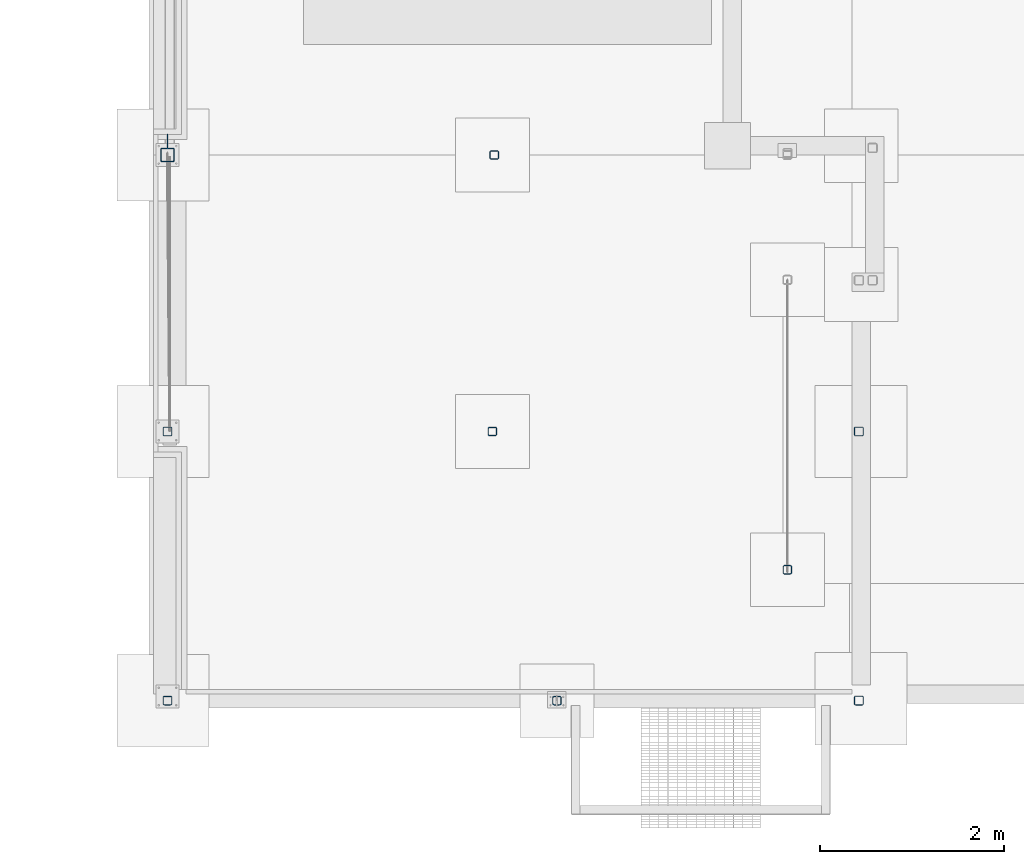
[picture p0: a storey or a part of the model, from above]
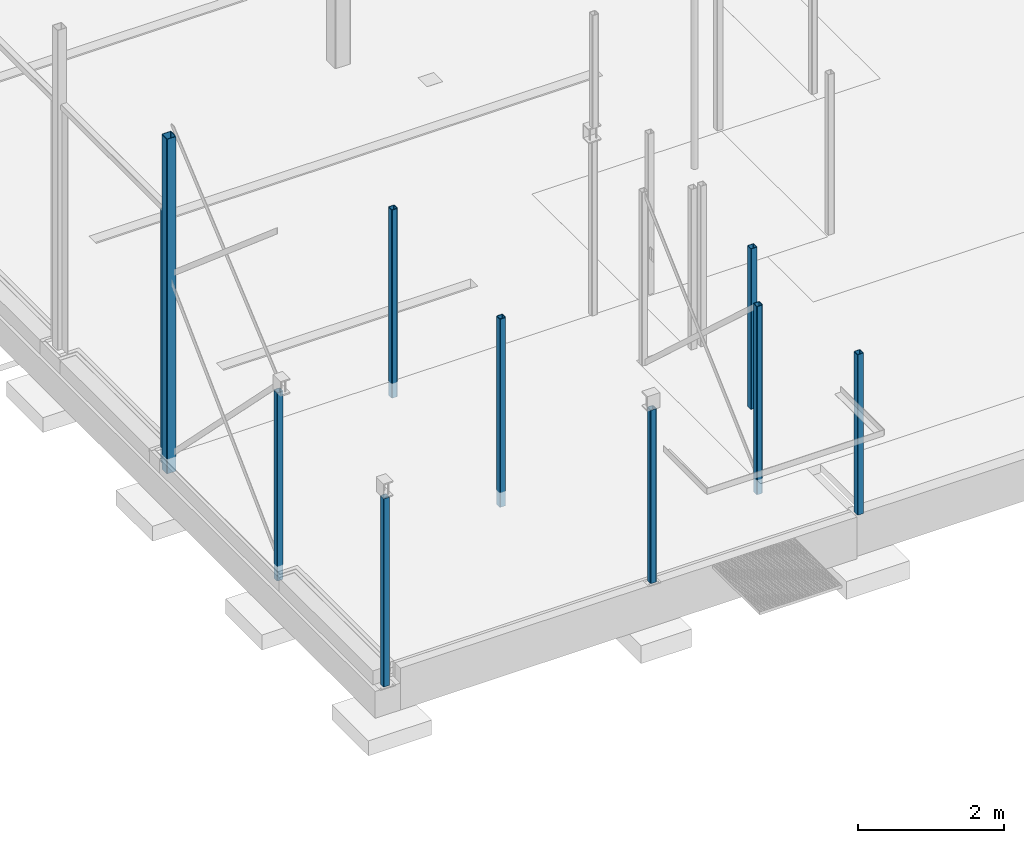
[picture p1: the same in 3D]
Properties of the parts of a building model (IFC2X3)

# File
Description: ViewDefinition [CoordinationView_V2.0]
File name: 17-036
Time: 2018-02-02T19:05:26
Written by: The EXPRESS Data Manager Version 5.02.0100.07 : 28 Aug 2013
Made in: 20170927_1515(x64) - Exporter 18.2.0.51 - Alternate UI 18.2.0.51
Comment: STEP Physical File produced by: The EXPRESS Data Manager Version 5.02.0100.07 : 28 Aug 2013 * Module: EDMstepFileFactory/EDMstandAlone * Creation date: Fri Feb 02 19:05:26 2018 * Host: DESKTOP-K52CJEA * Database: C:\Users\tt\AppData\Local\Temp\{7197A6A8-A7F9-4CEF-8441-73D635679DA6}\ifc * Database version: 5507 * Database creation date: Fri Feb 02 19:05:19 2018 * Schema: IFC2X3 * Model: DataRepository.ifc * Model creation date: Fri Feb 02 19:05:20 2018 * Header model: DataRepository.ifc_HeaderModel * Header model creation date: Fri Feb 02 19:05:20 2018 * EDMuser: sdai-user * EDMgroup: sdai-group * License ID and type: 5605 : Permanent license. Expiry date: * EDMstepFileFactory options: 020000

# IfcProject, 17-036
LongName: BRANNSTASJON GJESDAL

# IfcSite, Default
RefLatitude: 59, 54, 57, 599999; RefLongitude: 10, 44, 59, 999999; RefElevation: 101000 mm

# IfcBuildingStorey (3)
Procon - Type: Nivå 8mm Project
Name | LongName | Elevation (mm)
01 | 01 | 8.92956e-10
02 | 02 | 3150
03 | 03 | 6025

# IfcBeam: Bjelke HE:HE 240 A (3)
In: 03
Type - PredefinedType: BEAM
Material: Stål - S355
Pset_VDC - Fase: New Construction
Procon - Type: HE 240 A; s: 7.5 mm; B: 240 mm; h: 230 mm; b: 240 mm; Materiale: S355
Name (Bjelke HE:HE 240 A:...)
871638
872002
872111

# IfcBeam: Bjelke HE:HE 320 A, Bjelke HE:HE 320 A:870872
In: 03
Type - PredefinedType: BEAM
Material: Stål - S355
Pset_VDC - Fase: New Construction
Procon - Type: HE 320 A; s: 9 mm; B: 300 mm; h: 310 mm; b: 300 mm; Materiale: S355

# IfcBeam: Bjelke HUP:HUP 100x100x5 (8)
Type - PredefinedType: BEAM
Procon - Type: HUP 100x100x5; B: 100 mm; h: 100 mm; b: 100 mm
Name (Bjelke HUP:HUP 100x100x5:...) | In | Material = Materiale | Fase
892867 | 01 | S355 | New Construction
892922 | 01 | S355 | New Construction
892962 | 01 | S355 | New Construction
907845 | 03 |  | Existing
912680 | 03 |  | Existing
912808 | 03 |  | Existing
943207 | 02 | S355 | New Construction
957486 | 02 | S355 | New Construction

# IfcBeam: Bjelke HUP:HUP 100x100x6.3, Bjelke HUP:HUP 100x100x6.3:958355
In: 02
Type - PredefinedType: BEAM
Material: S355
Pset_VDC - Fase: New Construction
Procon - Type: HUP 100x100x6.3; B: 100 mm; h: 100 mm; b: 100 mm; Materiale: S355

# IfcBeam: Bjelke HUP:HUP 100x50x5 (4)
In: 01
Type - PredefinedType: BEAM
Material: S355
Procon - Type: HUP 100x50x5; B: 50 mm; h: 100 mm; b: 50 mm; Materiale: S355
Name (Bjelke HUP:HUP 100x50x5:...) | Fase
834604 | Existing
834900 | Existing
848106 | New Construction
848423 | New Construction

# IfcBeam: Bjelke HUP:HUP 120x120x5 (17)
Type - PredefinedType: BEAM
Material: S355
Procon - Type: HUP 120x120x5; B: 120 mm; h: 120 mm; b: 120 mm; Materiale: S355
Name (Bjelke HUP:HUP 120x120x5:...) | In | Fase
835029 | 01 | Existing
835167 | 01 | Existing
842518 | 03 | Existing
848209 | 01 | Existing
853000 | 03 | Existing
856602 | 03 | Existing
857134 | 03 | Existing
885489 | 03 | New Construction
885869 | 02 | New Construction
907847 | 03 | Existing
909423 | 03 | Existing
912682 | 03 | Existing
912734 | 03 | Existing
912810 | 03 | Existing
912862 | 03 | Existing
941562 | 03 | New Construction
983510 | 03 | New Construction

# IfcBeam: Bjelke HUP:HUP 200x100x8, Bjelke HUP:HUP 200x100x8:880046
In: 01
Type - PredefinedType: BEAM
Material: S355
Pset_VDC - Fase: New Construction
Procon - Type: HUP 200x100x8; B: 100 mm; h: 200 mm; b: 100 mm; Materiale: S355

# IfcBeam: Bjelke IPE:IPE 200 (7)
Type - PredefinedType: BEAM
Material: Stål - S355
Procon - Type: IPE 200; s: 5.6 mm; B: 100 mm; h: 200 mm; b: 100 mm
Name (Bjelke IPE:IPE 200:...) | In | Fase | Materiale
827796 | 02 | Existing | B500C
827884 | 02 | Existing | S355
828458 | 02 | New Construction | B500C
828737 | 02 | Existing | S355
849826 | 03 | Existing | B500C
850250 | 03 | Existing | B500C
883743 | 02 | New Construction | S355

# IfcBeam: Bjelke IPE:IPE 220 (2)
In: 03
Type - PredefinedType: BEAM
Material: Stål - S355
Pset_VDC - Fase: New Construction
Procon - Type: IPE 220; s: 5.6 mm; B: 110 mm; h: 220 mm; b: 110 mm; Materiale: S355
Name (Bjelke IPE:IPE 220:...)
871949
872135

# IfcBeam: Bjelke Stålplate:40x5 mm (6)
Type - PredefinedType: BEAM
Material: Structural Framing Fireproofing
Pset_VDC - Fase: Existing
Procon - Type: 40x5 mm; B: 5 mm; h: 40 mm; b: 5 mm; Materiale: B500C
Name (Bjelke Stålplate:40x5 mm:...) | In
840561 | 01
840626 | 01
860526 | 02
860853 | 02
861374 | 02
861407 | 02

# IfcBeam: Bjelke Stålplate:VINDKRYSS (31)
Type - PredefinedType: BEAM
Material: Structural Framing Fireproofing
Procon - Type: VINDKRYSS; B: 8 mm; h: 80 mm; b: 8 mm; Materiale: S355
Name (Bjelke Stålplate:VINDKRYSS:...) | In | Fase
837247 | 01 | Existing
837501 | 01 | Existing
837691 | 01 | Existing
837693 | 01 | Existing
839909 | 01 | Existing
840269 | 01 | Existing
848571 | 01 | Existing
848618 | 01 | Existing
848719 | 01 | Existing
848820 | 01 | Existing
849208 | 01 | Existing
849243 | 01 | Existing
862490 | 01 | Existing
862522 | 01 | Existing
862570 | 01 | Existing
862615 | 01 | Existing
863401 | 02 | Existing
863636 | 02 | Existing
863878 | 02 | Existing
864032 | 01 | New Construction
864350 | 02 | Existing
864864 | 01 | New Construction
936087 | 01 | New Construction
936169 | 01 | New Construction
936714 | 01 | New Construction
936716 | 01 | New Construction
956203 | 01 | New Construction
956450 | 01 | New Construction
985487 | 01 | New Construction
985516 | 01 | New Construction
985939 | 01 | New Construction

# IfcBuildingElementProxy (2)
In: 01
Pset_VDC - Fase: New Construction

# IfcBuildingElementProxy: 1000x600, Rist:1000x600:979838
In: 01
Type - Material: Metal - Steel - ASTM A36
Pset_VDC - Fase: New Construction
Procon - Type: 1000x600

# IfcBuildingElementProxy: 110x110 (2)
In: 01
Type - Material: Stål - S355
Pset_VDC - Fase: New Construction
Procon - Type: 110x110; Bruk: Innstøpningsplate
Name (stegforsterker:110x110:...)
1004790
1005038

# IfcBuildingElementProxy: 1300x1300, Rist:1300x1300:979612
In: 01
Type - Material: Metal - Steel - ASTM A36
Pset_VDC - Fase: New Construction
Procon - Type: 1300x1300

# IfcBuildingElementProxy: 146x279 (2)
In: 01
Type - Material: Stål - S355
Pset_VDC - Fase: New Construction
Procon - Type: 146x279; Bruk: Innstøpningsplate
Name (stegforsterker:146x279:...)
1004614
1004708

# IfcBuildingElementProxy: 150x200x15, Innstøpningsplate_uten klør_4hull:150x200x15:1005573
In: 01
Type - Material: S355
Pset_VDC - Fase: New Construction
Procon - Type: 150x200x15; Bruk: Innstøpningsplate

# IfcBuildingElementProxy: 200x150 (4)
In: 01
Type - Material: S355
Pset_VDC - Fase: New Construction
Procon - Type: 200x150
Name (Innstøpningsplate mk.3:200x150:...)
964004
964119
964160
964293

# IfcBuildingElementProxy: 250x250x15 (7)
In: 01
Type - Material: S355
Pset_VDC - Fase: New Construction
Procon - Type: 250x250x15; Bruk: Innstøpningsplate
Name (Innstøpningsplate_uten klør_4hull:250x250x15:...)
965362
965550
965639
965659
965679
965702
965728

# IfcBuildingElementProxy: 400x400x15, Innstøpningsplate_uten klør_4hull:400x400x15:965898
In: 01
Type - Material: Stål - S355
Pset_VDC - Fase: New Construction
Procon - Type: 400x400x15; Bruk: Innstøpningsplate

# IfcBuildingElementProxy: 52x203 (2)
In: 01
Type - Material: Stål - S355
Pset_VDC - Fase: New Construction
Procon - Type: 52x203; Bruk: Innstøpningsplate
Name (stegforsterker:52x203:...)
1003703
1005512

# IfcBuildingElementProxy: L 100x100x8 (3)
In: 01
Type - Material: Stål - S355
Pset_VDC - Fase: New Construction
Procon - Type: L 100x100x8; B: 100 mm; b: 100 mm; d: 100 mm; Materiale: Stål - S355
Name (Bjelke L (Linebased):L 100x100x8:...)
960560
960701
960818

# IfcBuildingElementProxy: RIB, Procon_Prosjekt nullpunkt RIB:RIB:696122
In: 01
Material: NULPUNKT - RIB, Default
Pset_VDC - LOD: 200; MMI: 300; Fase: New Construction
Procon - Type: RIB; Bruk: Prosjekt nullpunkt

# IfcBuildingElementProxy: SPL 530x300, Innstøpningsplate_PLANE:SPL 530x300:999380
In: 01
Type - Material: Stål - S355
Pset_VDC - Fase: New Construction
Procon - Type: SPL 530x300; Bruk: Innstøpningsplate

# IfcBuildingElementProxy: Slab Edge:50x235 (2)
In: 01
Pset_VDC - Fase: New Construction
Procon - Type: 50x235

# IfcBuildingElementProxy: Slab Edge:L-PROFIL (11)
In: 01
Pset_VDC - Fase: New Construction
Procon - Type: L-PROFIL

# IfcColumn: BRANNMANNSTANG, Søyle Sirkulær:BRANNMANNSTANG:953777
In: 01
Type - ElementType: BRANNMANNSTANG; PredefinedType: COLUMN; Material: Barco_Cromado
Pset_VDC - Fase: New Construction
Procon - Type: BRANNMANNSTANG; d: 101.6 mm; Materiale: Barco_Cromado

# IfcColumn: HUP 100x100x10 (17)
Type - ElementType: HUP 100x100x10; PredefinedType: COLUMN; Material: S355
Pset_VDC - Fase: New Construction
Procon - Type: HUP 100x100x10; B: 100 mm; h: 100 mm; b: 100 mm; Materiale: S355
Name (Søyle HUP:HUP 100x100x10:...) | In
868132 | 01
868171 | 01
870031 | 01
870124 | 01
870175 | 01
877240 | 01
883108 | 02
884206 | 01
884350 | 01
884389 | 01
884412 | 01
884435 | 01
888171 | 01
919263 | 01
939634 | 01
998223 | 02
998225 | 02

# IfcColumn: HUP 100x100x6.3 (49)
Type - ElementType: HUP 100x100x6.3; PredefinedType: COLUMN; Material: S355
Procon - Type: HUP 100x100x6.3; B: 100 mm; h: 100 mm; b: 100 mm; Materiale: S355
Name (Søyle HUP:HUP 100x100x6.3:...) | In | Fase
817394 | 01 | Existing
817816 | 01 | Existing
817874 | 01 | Existing
817895 | 01 | Existing
817935 | 01 | Existing
818292 | 01 | Existing
818311 | 01 | Existing
818334 | 01 | Existing
818351 | 01 | Existing
818370 | 01 | Existing
818389 | 01 | Existing
818408 | 01 | Existing
818427 | 01 | Existing
818446 | 01 | Existing
818465 | 01 | Existing
818529 | 01 | Existing
818574 | 01 | Existing
818593 | 01 | Existing
822377 | 02 | Existing
822912 | 02 | Existing
822927 | 02 | Existing
822942 | 02 | Existing
822972 | 02 | Existing
822987 | 02 | Existing
823002 | 02 | Existing
823017 | 02 | Existing
823032 | 02 | Existing
823098 | 02 | Existing
823113 | 02 | Existing
823177 | 02 | Existing
823192 | 02 | Existing
823207 | 02 | Existing
836697 | 01 | Existing
842414 | 02 | Existing
859931 | 03 | New Construction
889985 | 03 | New Construction
922079 | 03 | New Construction
961115 | 02 | New Construction
961629 | 02 | New Construction
983055 | 03 | New Construction
983187 | 03 | New Construction
989898 | 01 | Existing
992850 | 02 | Existing
992885 | 02 | Existing
992922 | 02 | Existing
992947 | 02 | Existing
993013 | 02 | Existing
993061 | 02 | Existing
993143 | 02 | Existing

# IfcColumn: HUP 100x100x8 (4)
Type - ElementType: HUP 100x100x8; PredefinedType: COLUMN; Material: S355
Pset_VDC - Fase: New Construction
Procon - Type: HUP 100x100x8; B: 100 mm; h: 100 mm; b: 100 mm; Materiale: S355
Name (Søyle HUP:HUP 100x100x8:...) | In
871523 | 01
871560 | 01
883363 | 02
883453 | 02

# IfcColumn: HUP 150x150x6 (+1x150x10) (2)
In: 01
Type - ElementType: HUP 150x150x6 (+1x150x10); PredefinedType: COLUMN; Material: S355
Pset_VDC - Fase: New Construction
Procon - Type: HUP 150x150x6 (+1x150x10); B: 150 mm; h: 150 mm; b: 150 mm; Materiale: S355
Name (Søyle HUP_1ving:HUP 150x150x6 (+1x150x10):...)
867908
898764

# IfcColumn: HUP 150x150x6 (+2x150x10) (3)
In: 01
Type - ElementType: HUP 150x150x6 (+2x150x10); PredefinedType: COLUMN; Material: S355
Pset_VDC - Fase: New Construction
Procon - Type: HUP 150x150x6 (+2x150x10); B: 150 mm; h: 150 mm; b: 150 mm; Materiale: S355
Name (Søyle HUP_ving:HUP 150x150x6 (+2x150x10):...)
871430
871477
876422

# IfcColumn: HUP 250x250, Søyle HUP:HUP 250x250:869183
In: 01
Type - ElementType: HUP 250x250; PredefinedType: COLUMN; Material: S355
Pset_VDC - Fase: New Construction
Procon - Type: HUP 250x250; B: 250 mm; h: 250 mm; b: 250 mm; Materiale: S355

# IfcElementAssembly: Gitterdrager:Standard (3)
In: 03
PredefinedType: TRUSS
Pset_VDC - Fase: Existing
Procon - Type: Standard
Name (Gitterdrager:Standard:...)
907843
912679
912807

# IfcFlowTerminal: 6" Diameter (2)
In: 01
Material: Fixtures - Avløp - Chrome, Fixtures - Avløp
Pset_VDC - Fase: New Construction
Procon - Type: 6" Diameter
Name (Sluk:6" Diameter:...) | Vert
967741 | 1
967910 | 2

# IfcMember: 60x60x5 (69)
In: 03
Type - ElementType: 60x60x5; PredefinedType: BRACE
Pset_VDC - Fase: Existing
Procon - Type: 60x60x5; B: 60 mm; h: 60 mm; b: 60 mm
Name (Bjelke HUP:60x60x5:...)
908123
908125
908127
908129
908131
908133
908135
908137
908139
908141
908143
908145
908147
908149
908151
908153
908155
908157
908159
908161
908163
908165
908167
912688
912690
912692
912694
912696
912698
912700
912702
912704
912706
912708
912710
912712
912714
912716
912718
912720
912722
912724
912726
912728
912730
912732
912816
912818
912820
912822
912824
912826
912828
912830
912832
912834
912836
912838
912840
912842
912844
912846
912848
912850
912852
912854
912856
912858
912860

# IfcOpeningElement: Opening (5)
In: 01
Name | Fase | Type | OD Generelt | Materiale
Basic Wall:OPPKANT B=200, (140):805795 | Existing | OPPKANT B=200, (140) | Rebar Cover Settings: 25 mm | Betong Plasstøpt - B35 | Procon - OD Innvendig: Rebar Cover Settings: 25 mm; OD Utvendig: Rebar Cover Settings: 25 mm
Basic Wall:OPPKANT B=200, (140):810791 | Existing | OPPKANT B=200, (140) | Rebar Cover Settings: 25 mm | Betong Plasstøpt - B35 | Procon - OD Innvendig: Rebar Cover Settings: 25 mm; OD Utvendig: Rebar Cover Settings: 25 mm
2 x 
Basic Wall:ACODRAIN 200:971086:1 | New Construction | ACODRAIN 200 | Rebar Cover Settings: 25 mm | Betong Plasstøpt - B35

# IfcSlab: Floor:BETONG 100 (3)
In: 01
PredefinedType: FLOOR; Material: Betong Plasstøpt - B35 100 mm
Pset_VDC - Fase: New Construction
Procon - Type: BETONG 100; OD Topp: Rebar Cover Settings: 25 mm; OD Bunn: Rebar Cover Settings: 25 mm; OD Generelt: Rebar Cover Settings: 25 mm; Bruk: Betongdekke; Materiale: Betong Plasstøpt - B35
Name (Floor:BETONG 100:...)
948453
949808
953002

# IfcSlab: Floor:BETONG 150, Floor:BETONG 150:949454
In: 01
PredefinedType: FLOOR; Material: Betong Plasstøpt - B30 150 mm
Pset_VDC - Fase: New Construction
Procon - Type: BETONG 150; OD Topp: Rebar Cover Settings: 25 mm; OD Bunn: Rebar Cover Settings: 25 mm; OD Generelt: Rebar Cover Settings: 25 mm; Bruk: Betongdekke; Materiale: Betong Plasstøpt - B30

# IfcSlab: Floor:BETONG 250, Floor:BETONG 250:877322
In: 02
PredefinedType: FLOOR; Material: Betong Plasstøpt - B35
Pset_VDC - Fase: New Construction
Procon - Type: BETONG 250; OD Topp: Rebar Cover Settings: 25 mm; OD Bunn: Rebar Cover Settings: 25 mm; OD Generelt: Rebar Cover Settings: 25 mm; Bruk: Betongdekke; Materiale: Betong Plasstøpt - B35

# IfcSlab: Floor:BETONG 70+50, Floor:BETONG 70+50:816883
In: 01
PredefinedType: FLOOR; Material: Betong Plasstøpt - B30 70 mm, EPS 50 mm
Pset_VDC - Fase: Existing
Procon - Type: BETONG 70+50; OD Topp: Rebar Cover Settings: 25 mm; OD Bunn: Rebar Cover Settings: 25 mm; OD Generelt: Rebar Cover Settings: 25 mm; Bruk: Betongdekke; Materiale: Betong Plasstøpt - B30

# IfcSlab: Floor:EPS 100 (2)
In: 01
PredefinedType: FLOOR; Material: EPS 100 mm
Pset_VDC - Fase: New Construction
Procon - Type: EPS 100; Bruk: Betongdekke; Materiale: EPS
Name (Floor:EPS 100:...)
969534 | Procon - OD Topp: Rebar Cover Settings: 25 mm; OD Bunn: Rebar Cover Settings: 25 mm; OD Generelt: Rebar Cover Settings: 25 mm
969641

# IfcSlab: Floor:EPS 50 (2)
In: 01
PredefinedType: FLOOR; Material: EPS 50 mm
Pset_VDC - Fase: New Construction
Procon - Type: EPS 50; OD Bunn: Rebar Cover Settings: 25 mm; OD Generelt: Rebar Cover Settings: 25 mm; Bruk: Betongdekke; Materiale: EPS
Name (Floor:EPS 50:...)
968577
968859 | Procon - OD Topp: Rebar Cover Settings: 25 mm

# IfcSlab: Floor:HD-265, Floor:HD-265:828784
In: 02
PredefinedType: FLOOR; Material: HD1200mm 265 mm
Pset_VDC - Fase: Existing
Procon - Type: HD-265; OD Topp: Rebar Cover Settings: 25 mm; OD Bunn: Rebar Cover Settings: 25 mm; OD Generelt: Rebar Cover Settings: 25 mm; Bruk: Hulldekker; Materiale: HD1200mm

# IfcSlab: Floor:PLANNJA 111.5, Floor:PLANNJA 111.5:957842
In: 02
PredefinedType: FLOOR; Material: Structural Steel - S235 111.5 mm
Pset_VDC - Fase: New Construction
Procon - Type: PLANNJA 111.5; OD Topp: Rebar Cover Settings: 25 mm; OD Bunn: Rebar Cover Settings: 25 mm; OD Generelt: Rebar Cover Settings: 25 mm; Bruk: Betongdekke; Materiale: Structural Steel - S235

# IfcSlab: Floor:PÅSTØP 160 VARIABEL, Floor:PÅSTØP 160 VARIABEL:885118
In: 01
PredefinedType: FLOOR; Material: Betong Plasstøpt - B30
Pset_VDC - Fase: New Construction
Procon - Type: PÅSTØP 160 VARIABEL; OD Topp: Rebar Cover Settings: 25 mm; OD Bunn: Rebar Cover Settings: 25 mm; OD Generelt: Rebar Cover Settings: 25 mm; Bruk: Betongdekke; Materiale: Betong Plasstøpt - B30

# IfcSlab: Floor:TRP 170, Floor:TRP 170:982709
In: 03
PredefinedType: FLOOR; Material: Structural Steel - S235 170 mm
Pset_VDC - Fase: New Construction
Procon - Type: TRP 170; OD Topp: Rebar Cover Settings: 25 mm; OD Bunn: Rebar Cover Settings: 25 mm; OD Generelt: Rebar Cover Settings: 25 mm; Bruk: Betongdekke; Materiale: Structural Steel - S235

# IfcSlab: Fundament med knast:800x800x300 (4)
In: 01
PredefinedType: FLOOR; Material: Betong Plasstøpt - B35
Pset_VDC - Fase: Existing
Procon - Type: 800x800x300; OD Topp: Rebar Cover Settings: 25 mm; OD Bunn: Rebar Cover Settings: 25 mm; OD Generelt: Rebar Cover Settings: 25 mm; Bruk: Punktfundament; Materiale: Betong Plasstøpt - B35
Name (Fundament med knast:800x800x300:...)
811937
812203
812445
945172

# IfcSlab: Punktfundament:1000x1000x250 (8)
In: 01
PredefinedType: FLOOR; Material: Betong Plasstøpt - B35
Pset_VDC - Fase: New Construction
Procon - Type: 1000x1000x250; OD Topp: Rebar Cover Settings: 25 mm; OD Bunn: Rebar Cover Settings: 25 mm; OD Generelt: Rebar Cover Settings: 25 mm; Bruk: Punktfundament; Materiale: Betong Plasstøpt - B35
Name (Punktfundament:1000x1000x250:...)
903198
903367
903390
903418
903443
903478
903499
922697

# IfcSlab: Punktfundament:1800x800x300, Punktfundament:1800x800x300:813598
In: 01
PredefinedType: FLOOR; Material: Betong Plasstøpt - B35
Pset_VDC - Fase: Existing
Procon - Type: 1800x800x300; OD Topp: Rebar Cover Settings: 25 mm; OD Bunn: Rebar Cover Settings: 25 mm; OD Generelt: Rebar Cover Settings: 25 mm; Bruk: Punktfundament; Materiale: Betong Plasstøpt - B35

# IfcSlab: Punktfundament:500x500x300 (4)
In: 01
PredefinedType: FLOOR; Material: Betong Plasstøpt - B35
Pset_VDC - Fase: New Construction
Procon - Type: 500x500x300; OD Topp: Rebar Cover Settings: 25 mm; OD Bunn: Rebar Cover Settings: 25 mm; OD Generelt: Rebar Cover Settings: 25 mm; Bruk: Punktfundament; Materiale: Betong Plasstøpt - B35
Name (Punktfundament:500x500x300:...)
812942
813215
813320
813399

# IfcSlab: Punktfundament:800x800x300 (16)
In: 01
PredefinedType: FLOOR; Material: Betong Plasstøpt - B35
Pset_VDC - Fase: New Construction
Procon - Type: 800x800x300; OD Topp: Rebar Cover Settings: 25 mm; OD Bunn: Rebar Cover Settings: 25 mm; OD Generelt: Rebar Cover Settings: 25 mm; Bruk: Punktfundament; Materiale: Betong Plasstøpt - B35
Name (Punktfundament:800x800x300:...)
811412
811774
812678
943839
943852
943875
943892
943931
944027
944042
945478
945835
945862
945887
962320
962342

# IfcSlab: Punktfundament:Betong 1000x1000x300mm (14)
In: 01
PredefinedType: FLOOR; Material: Betong Plasstøpt - B35
Procon - Type: Betong 1000x1000x300mm; OD Topp: Rebar Cover Settings: 25 mm; OD Bunn: Rebar Cover Settings: 25 mm; OD Generelt: Rebar Cover Settings: 25 mm; Bruk: Punktfundament; Materiale: Betong Plasstøpt - B35
Name (Punktfundament:Betong 1000x1000x300mm:...) | Fase
807751 | Existing
807992 | Existing
808117 | Existing
808202 | Existing
808359 | Existing
808446 | Existing
808525 | Existing
808620 | Existing
808726 | New Construction
808916 | New Construction
809057 | New Construction
809176 | New Construction
809325 | Existing
809442 | New Construction

# IfcWall: Basic Wall:OPPKANT 400, Basic Wall:OPPKANT 400:900278
In: 01
Material: Betong Plasstøpt - B35
Pset_VDC - Fase: New Construction
Procon - Type: OPPKANT 400; OD Innvendig: Rebar Cover Settings: 25 mm; OD Utvendig: Rebar Cover Settings: 25 mm; OD Generelt: Rebar Cover Settings: 25 mm; Materiale: Betong Plasstøpt - B35

# IfcWall: Basic Wall:OPPKANT B=200, Basic Wall:OPPKANT B=200:900447
In: 01
Type - PredefinedType: STANDARD; Material: Betong Plasstøpt - B35 200 mm
Pset_VDC - Fase: New Construction
Procon - Type: OPPKANT B=200; OD Innvendig: Rebar Cover Settings: 25 mm; OD Utvendig: Rebar Cover Settings: 25 mm; OD Generelt: Rebar Cover Settings: 25 mm; Materiale: Betong Plasstøpt - B35

# IfcWallStandardCase: Basic Wall:ACODRAIN 200 (4)
In: 01
Type - PredefinedType: STANDARD; Material: Betong Plasstøpt - B35 600 mm
Pset_VDC - Fase: New Construction
Procon - Type: ACODRAIN 200; OD Generelt: Rebar Cover Settings: 25 mm; Materiale: Betong Plasstøpt - B35
Name (Basic Wall:ACODRAIN 200:...)
970487
971029
971086
971308

# IfcWallStandardCase: Basic Wall:BETONG 200, Basic Wall:BETONG 200:815344
In: 01
Type - PredefinedType: STANDARD; Material: Betong Plasstøpt - B35 200 mm
Pset_VDC - Fase: Existing
Procon - Type: BETONG 200; OD Innvendig: Rebar Cover Settings: 25 mm; OD Utvendig: Rebar Cover Settings: 25 mm; OD Generelt: Rebar Cover Settings: 25 mm; Materiale: Betong Plasstøpt - B35

# IfcWallStandardCase: Basic Wall:OPPKANT B=200, Basic Wall:OPPKANT B=200:900350
In: 01
Type - PredefinedType: STANDARD; Material: Betong Plasstøpt - B35 200 mm
Pset_VDC - Fase: New Construction
Procon - Type: OPPKANT B=200; OD Innvendig: Rebar Cover Settings: 25 mm; OD Utvendig: Rebar Cover Settings: 25 mm; OD Generelt: Rebar Cover Settings: 25 mm; Materiale: Betong Plasstøpt - B35

# IfcWallStandardCase: Basic Wall:OPPKANT B=200, (140) (12)
In: 01
Type - PredefinedType: STANDARD; Material: Betong Plasstøpt - B35 200 mm
Pset_VDC - Fase: Existing
Procon - Type: OPPKANT B=200, (140); OD Innvendig: Rebar Cover Settings: 25 mm; OD Utvendig: Rebar Cover Settings: 25 mm; OD Generelt: Rebar Cover Settings: 25 mm; Materiale: Betong Plasstøpt - B35
Name (Basic Wall:OPPKANT B=200, (140):...)
804726
805097
805292
805795
806116
807057
807259
810111
810346
810445
810661
810791

# IfcWallStandardCase: Basic Wall:OPPKANT B=250+50 (5)
In: 01
Type - PredefinedType: STANDARD; Material: Betong Plasstøpt - B35 250 mm
Pset_VDC - Fase: New Construction
Procon - Type: OPPKANT B=250+50; OD Innvendig: Rebar Cover Settings: 25 mm; OD Utvendig: Rebar Cover Settings: 25 mm; OD Generelt: Rebar Cover Settings: 25 mm; Materiale: Betong Plasstøpt - B35
Name (Basic Wall:OPPKANT B=250+50:...)
901914
915300
915484
915678
940474
